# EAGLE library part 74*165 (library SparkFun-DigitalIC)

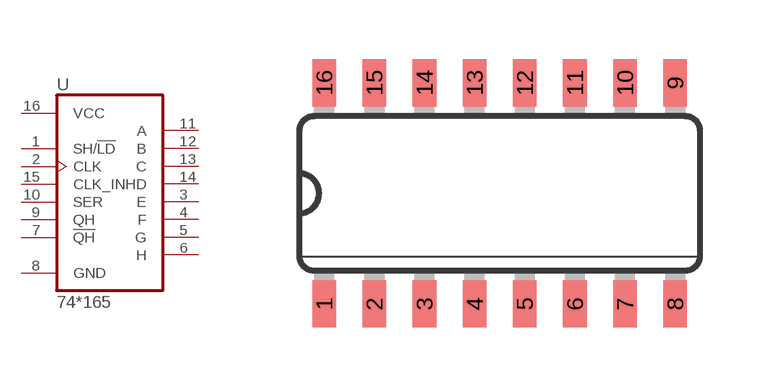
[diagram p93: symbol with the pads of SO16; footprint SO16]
Designator prefix -

## 74165D  [SO16]
1  SH/!LD  in
2  CLK  in
3  E  hiz
4  F  hiz
5  G  hiz
6  H  hiz
7  !QH  in
8  GND  pwr
9  QH  hiz
10  SER  in
11  A  hiz
12  B  hiz
13  C  hiz
14  D  hiz
15  CLK_INH  in
16  VCC  pwr

## Footprint SO16 (pad centres in mm)
Small Outline package 150 mil
smd 0.6 x 1.2: 1 -4.445,-2.8; 2 -3.175,-2.8; 3 -1.905,-2.8; 4 -0.635,-2.8; 5 0.635,-2.8; 6 1.905,-2.8; 7 3.175,-2.8; 8 4.445,-2.8; 9 4.445,2.8; 10 3.175,2.8; 11 1.905,2.8; 12 0.635,2.8; 13 -0.635,2.8; 14 -1.905,2.8; 15 -3.175,2.8; 16 -4.445,2.8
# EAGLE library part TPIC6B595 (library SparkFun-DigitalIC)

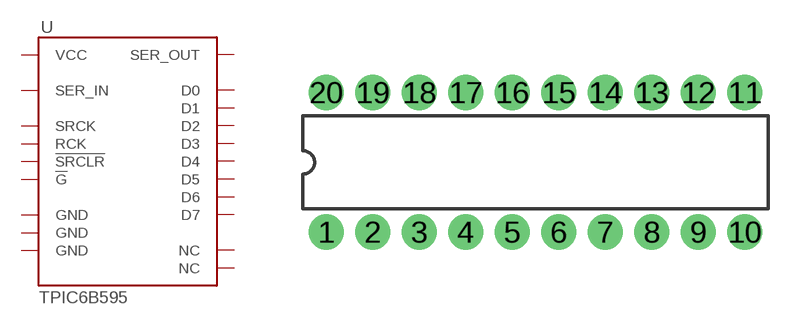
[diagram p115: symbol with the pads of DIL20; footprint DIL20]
Designator prefix U

## TPIC6B595PTH  [DIL20]
1  NC  nc
2  VCC  pwr
3  SER_IN  in
4  D0  out
5  D1  out
6  D2  out
7  D3  out
8  !SRCLR  in
9  !G  in
10  GND  pwr
11  GND  pwr
12  RCK  in
13  SRCK  in
14  D4  out
15  D5  out
16  D6  out
17  D7  out
18  SER_OUT  out
19  GND  pwr
20  NC  nc

## Footprint DIL20 (pad centres in mm)
drill 1.016 pad 1.93: 1 -11.43,-3.81; 2 -8.89,-3.81; 3 -6.35,-3.81; 4 -3.81,-3.81; 5 -1.27,-3.81; 6 1.27,-3.81; 7 3.81,-3.81; 8 6.35,-3.81; 9 8.89,-3.81; 10 11.43,-3.81; 11 11.43,3.81; 12 8.89,3.81; 13 6.35,3.81; 14 3.81,3.81; 15 1.27,3.81; 16 -1.27,3.81; 17 -3.81,3.81; 18 -6.35,3.81; 19 -8.89,3.81; 20 -11.43,3.81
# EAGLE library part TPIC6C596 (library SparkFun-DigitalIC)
SMD version of the popular sink driver. This version can sink up to 100mA per channel

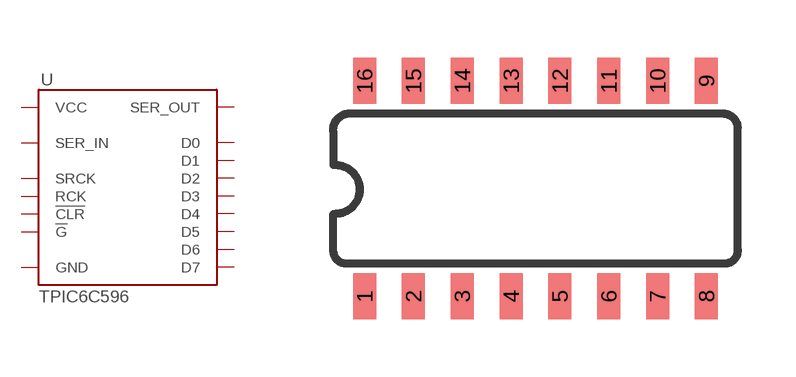
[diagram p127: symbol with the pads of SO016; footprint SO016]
Designator prefix U

## TPIC6C596SOIC (PROD_ID: IC-12522; VALUE: TPIC6C596)  [SO016]
1  VCC  pwr
2  SER_IN  in
3  D0  out
4  D1  out
5  D2  out
6  D3  out
7  !CLR  in
8  !G  in
9  SER_OUT  out
10  RCK  in
11  D4  out
12  D5  out
13  D6  out
14  D7  out
15  SRCK  in
16  GND  pwr

## Footprint SO016 (pad centres in mm)
smd 0.6 x 1.2: 1 -4.445,-2.8; 2 -3.175,-2.8; 3 -1.905,-2.8; 4 -0.635,-2.8; 5 0.635,-2.8; 6 1.905,-2.8; 7 3.175,-2.8; 8 4.445,-2.8; 9 4.445,2.8; 10 3.175,2.8; 11 1.905,2.8; 12 0.635,2.8; 13 -0.635,2.8; 14 -1.905,2.8; 15 -3.175,2.8; 16 -4.445,2.8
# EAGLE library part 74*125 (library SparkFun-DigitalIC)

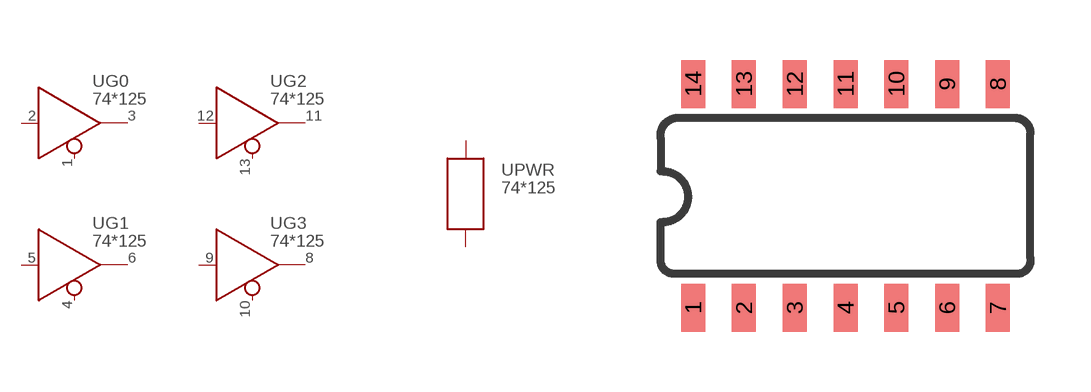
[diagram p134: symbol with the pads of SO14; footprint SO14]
Designator prefix U; gates G0=INVERTER_WITH_ENABLE G1=INVERTER_WITH_ENABLE G2=INVERTER_WITH_ENABLE G3=INVERTER_WITH_ENABLE PWR=POWER_PINS

## 74AC125DG125 (PROD_ID: IC-08880; VALUE: 74AC125)  [SO14]
1  G0:!EN
2  G0:D
3  G0:Q
4  G1:!EN
5  G1:D
6  G1:Q
7  PWR:P$V-
8  G3:Q
9  G3:D
10  G3:!EN
11  G2:Q
12  G2:D
13  G2:!EN
14  PWR:P$V+

## Footprint SO14 (pad centres in mm)
smd 0.6 x 1.2: 1 -3.81,-2.8; 2 -2.54,-2.8; 3 -1.27,-2.8; 4 0,-2.8; 5 1.27,-2.8; 6 2.54,-2.8; 7 3.81,-2.8; 8 3.81,2.8; 9 2.54,2.8; 10 1.27,2.8; 11 0,2.8; 12 -1.27,2.8; 13 -2.54,2.8; 14 -3.81,2.8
